VERSION 5.7 ;
  NOWIREEXTENSIONATPIN ON ;
  DIVIDERCHAR "/" ;
  BUSBITCHARS "[]" ;
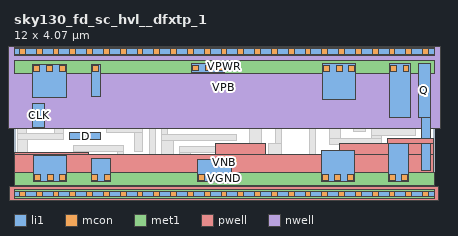
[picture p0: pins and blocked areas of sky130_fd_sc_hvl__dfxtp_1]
MACRO sky130_fd_sc_hvl__dfxtp_1
  CLASS BLOCK ;
  FOREIGN sky130_fd_sc_hvl__dfxtp_1 ;
  ORIGIN 0.000 0.000 ;
  SIZE 12.000 BY 4.070 ;
  PIN CLK
    ANTENNAGATEAREA 0.585000 ;
    PORT
      LAYER li1 ;
        RECT 0.540 1.905 0.870 2.575 ;
    END
  END CLK
  PIN D
    ANTENNAGATEAREA 0.420000 ;
    PORT
      LAYER li1 ;
        RECT 1.595 1.555 2.470 1.750 ;
    END
  END D
  PIN VGND
    USE GROUND ;
    PORT
      LAYER li1 ;
        RECT 0.560 0.365 1.510 1.095 ;
        RECT 2.200 0.365 2.765 1.025 ;
        RECT 5.255 0.365 6.205 0.995 ;
        RECT 8.780 0.365 9.730 1.245 ;
        RECT 10.690 0.365 11.280 1.495 ;
      LAYER mcon ;
        RECT 0.590 0.395 0.760 0.565 ;
        RECT 0.950 0.395 1.120 0.565 ;
        RECT 1.310 0.395 1.480 0.565 ;
        RECT 2.215 0.395 2.385 0.565 ;
        RECT 2.575 0.395 2.745 0.565 ;
        RECT 5.285 0.395 5.455 0.565 ;
        RECT 5.645 0.395 5.815 0.565 ;
        RECT 6.005 0.395 6.175 0.565 ;
        RECT 8.810 0.395 8.980 0.565 ;
        RECT 9.170 0.395 9.340 0.565 ;
        RECT 9.530 0.395 9.700 0.565 ;
        RECT 10.720 0.395 10.890 0.565 ;
        RECT 11.080 0.395 11.250 0.565 ;
      LAYER met1 ;
        RECT 0.000 0.255 12.000 0.625 ;
    END
  END VGND
  PIN VNB
    ANTENNADIFFAREA 2.040000 ;
    PORT
      LAYER pwell ;
        RECT 10.670 1.445 11.980 1.585 ;
        RECT 0.020 1.115 2.130 1.185 ;
        RECT 5.765 1.115 7.175 1.445 ;
        RECT 9.310 1.115 11.980 1.445 ;
        RECT 0.020 0.215 11.980 1.115 ;
        RECT -0.130 -0.215 12.130 0.215 ;
      LAYER li1 ;
        RECT 0.000 -0.085 12.000 0.085 ;
      LAYER mcon ;
        RECT 0.155 -0.085 0.325 0.085 ;
        RECT 0.635 -0.085 0.805 0.085 ;
        RECT 1.115 -0.085 1.285 0.085 ;
        RECT 1.595 -0.085 1.765 0.085 ;
        RECT 2.075 -0.085 2.245 0.085 ;
        RECT 2.555 -0.085 2.725 0.085 ;
        RECT 3.035 -0.085 3.205 0.085 ;
        RECT 3.515 -0.085 3.685 0.085 ;
        RECT 3.995 -0.085 4.165 0.085 ;
        RECT 4.475 -0.085 4.645 0.085 ;
        RECT 4.955 -0.085 5.125 0.085 ;
        RECT 5.435 -0.085 5.605 0.085 ;
        RECT 5.915 -0.085 6.085 0.085 ;
        RECT 6.395 -0.085 6.565 0.085 ;
        RECT 6.875 -0.085 7.045 0.085 ;
        RECT 7.355 -0.085 7.525 0.085 ;
        RECT 7.835 -0.085 8.005 0.085 ;
        RECT 8.315 -0.085 8.485 0.085 ;
        RECT 8.795 -0.085 8.965 0.085 ;
        RECT 9.275 -0.085 9.445 0.085 ;
        RECT 9.755 -0.085 9.925 0.085 ;
        RECT 10.235 -0.085 10.405 0.085 ;
        RECT 10.715 -0.085 10.885 0.085 ;
        RECT 11.195 -0.085 11.365 0.085 ;
        RECT 11.675 -0.085 11.845 0.085 ;
      LAYER met1 ;
        RECT 0.000 -0.115 12.000 0.115 ;
    END
  END VNB
  PIN VPB
    ANTENNADIFFAREA 2.040000 ;
    PORT
      LAYER nwell ;
        RECT -0.330 1.885 12.330 4.485 ;
      LAYER li1 ;
        RECT 0.000 3.985 12.000 4.155 ;
      LAYER mcon ;
        RECT 0.155 3.985 0.325 4.155 ;
        RECT 0.635 3.985 0.805 4.155 ;
        RECT 1.115 3.985 1.285 4.155 ;
        RECT 1.595 3.985 1.765 4.155 ;
        RECT 2.075 3.985 2.245 4.155 ;
        RECT 2.555 3.985 2.725 4.155 ;
        RECT 3.035 3.985 3.205 4.155 ;
        RECT 3.515 3.985 3.685 4.155 ;
        RECT 3.995 3.985 4.165 4.155 ;
        RECT 4.475 3.985 4.645 4.155 ;
        RECT 4.955 3.985 5.125 4.155 ;
        RECT 5.435 3.985 5.605 4.155 ;
        RECT 5.915 3.985 6.085 4.155 ;
        RECT 6.395 3.985 6.565 4.155 ;
        RECT 6.875 3.985 7.045 4.155 ;
        RECT 7.355 3.985 7.525 4.155 ;
        RECT 7.835 3.985 8.005 4.155 ;
        RECT 8.315 3.985 8.485 4.155 ;
        RECT 8.795 3.985 8.965 4.155 ;
        RECT 9.275 3.985 9.445 4.155 ;
        RECT 9.755 3.985 9.925 4.155 ;
        RECT 10.235 3.985 10.405 4.155 ;
        RECT 10.715 3.985 10.885 4.155 ;
        RECT 11.195 3.985 11.365 4.155 ;
        RECT 11.675 3.985 11.845 4.155 ;
      LAYER met1 ;
        RECT 0.000 3.955 12.000 4.185 ;
    END
  END VPB
  PIN VPWR
    USE POWER ;
    PORT
      LAYER li1 ;
        RECT 0.540 2.755 1.490 3.705 ;
        RECT 2.220 2.795 2.470 3.705 ;
        RECT 5.070 3.485 6.020 3.735 ;
        RECT 8.815 2.695 9.765 3.735 ;
        RECT 10.725 2.195 11.315 3.735 ;
      LAYER mcon ;
        RECT 0.570 3.505 0.740 3.675 ;
        RECT 0.930 3.505 1.100 3.675 ;
        RECT 1.290 3.505 1.460 3.675 ;
        RECT 2.250 3.505 2.420 3.675 ;
        RECT 5.100 3.515 5.270 3.685 ;
        RECT 5.460 3.515 5.630 3.685 ;
        RECT 5.820 3.515 5.990 3.685 ;
        RECT 8.845 3.505 9.015 3.675 ;
        RECT 9.205 3.505 9.375 3.675 ;
        RECT 9.565 3.505 9.735 3.675 ;
        RECT 10.755 3.505 10.925 3.675 ;
        RECT 11.115 3.505 11.285 3.675 ;
      LAYER met1 ;
        RECT 0.000 3.445 12.000 3.815 ;
    END
  END VPWR
  PIN Q
    ANTENNADIFFAREA 0.596250 ;
    PORT
      LAYER li1 ;
        RECT 11.560 2.185 11.890 3.735 ;
        RECT 11.640 0.685 11.890 2.185 ;
    END
  END Q
  OBS
      LAYER li1 ;
        RECT 0.110 1.725 0.360 3.565 ;
        RECT 1.670 2.615 2.000 3.565 ;
        RECT 2.650 3.305 3.680 3.475 ;
        RECT 2.650 2.615 2.820 3.305 ;
        RECT 3.510 3.135 7.655 3.305 ;
        RECT 1.670 2.445 2.820 2.615 ;
        RECT 3.000 2.280 3.330 3.125 ;
        RECT 3.510 2.460 3.840 3.135 ;
        RECT 4.055 2.675 4.385 2.955 ;
        RECT 6.470 2.755 7.305 2.955 ;
        RECT 1.165 1.930 2.820 2.225 ;
        RECT 3.000 2.110 4.035 2.280 ;
        RECT 1.165 1.725 1.415 1.930 ;
        RECT 2.650 1.760 3.685 1.930 ;
        RECT 0.110 1.555 1.415 1.725 ;
        RECT 0.110 0.595 0.380 1.555 ;
        RECT 1.690 1.205 3.115 1.375 ;
        RECT 3.430 1.205 3.685 1.760 ;
        RECT 1.690 0.595 2.020 1.205 ;
        RECT 2.945 0.435 3.115 1.205 ;
        RECT 3.865 1.025 4.035 2.110 ;
        RECT 3.295 0.615 4.035 1.025 ;
        RECT 4.215 1.695 4.385 2.675 ;
        RECT 4.565 2.385 6.955 2.555 ;
        RECT 4.565 1.885 4.890 2.385 ;
        RECT 6.705 2.225 6.955 2.385 ;
        RECT 5.435 2.045 5.765 2.205 ;
        RECT 7.135 2.045 7.305 2.755 ;
        RECT 5.435 1.875 7.305 2.045 ;
        RECT 7.485 2.515 7.655 3.135 ;
        RECT 7.835 2.865 8.085 3.735 ;
        RECT 7.835 2.695 8.600 2.865 ;
        RECT 7.485 2.225 8.250 2.515 ;
        RECT 8.430 2.445 8.600 2.695 ;
        RECT 8.430 2.275 10.035 2.445 ;
        RECT 4.215 1.525 6.345 1.695 ;
        RECT 4.215 0.615 4.545 1.525 ;
        RECT 4.725 1.175 6.555 1.345 ;
        RECT 4.725 0.435 5.055 1.175 ;
        RECT 2.945 0.265 5.055 0.435 ;
        RECT 6.385 0.435 6.555 1.175 ;
        RECT 6.735 0.615 7.065 1.875 ;
        RECT 7.485 1.445 7.655 2.225 ;
        RECT 7.280 1.125 7.655 1.445 ;
        RECT 7.280 0.435 7.450 1.125 ;
        RECT 8.430 1.025 8.600 2.275 ;
        RECT 9.000 1.595 9.330 2.015 ;
        RECT 9.705 1.775 10.035 2.275 ;
        RECT 10.215 2.005 10.545 3.735 ;
        RECT 10.215 1.675 11.460 2.005 ;
        RECT 10.215 1.595 10.510 1.675 ;
        RECT 9.000 1.425 10.510 1.595 ;
        RECT 7.835 0.945 8.600 1.025 ;
        RECT 7.630 0.855 8.600 0.945 ;
        RECT 7.630 0.525 8.005 0.855 ;
        RECT 10.180 0.525 10.510 1.425 ;
        RECT 6.385 0.265 7.450 0.435 ;
  END
END sky130_fd_sc_hvl__dfxtp_1
END LIBRARY

